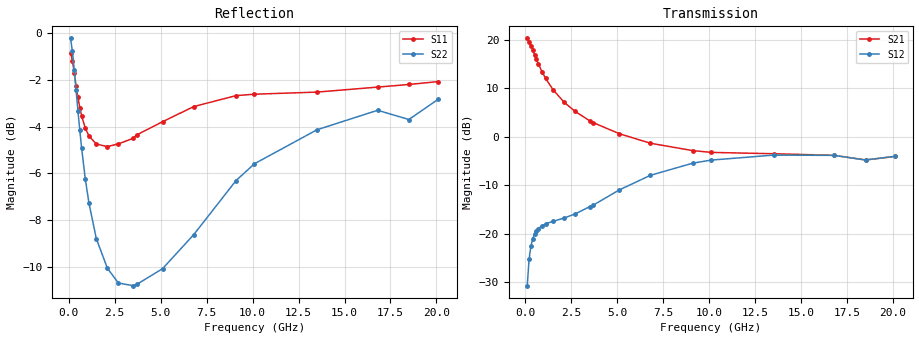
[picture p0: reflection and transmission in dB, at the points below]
!  Infineon Technologies AG
! BFR380L3 , PF131585-7, No.6, Th 09.10.01, soldered on pcb-board, measured with PP GSG850
!  Vce=3.0 V,  Ic=3.0 mA
! Common Emitter S-Parameters:  15. November 2001
#  GHz  S  MA  R  50
! f  S11  S21  S12  S22
! GHz  Mag  Ang  Mag  Ang  Mag  Ang  Mag  Ang
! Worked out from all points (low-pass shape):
!   201 points, 100 MHz to 20.1 GHz, reference 50 ohm
!   highest |S21| = 20.30 dB at 100 MHz (marker M1); lowest = -4.8 dB at 18.5 GHz (marker M2)
!   |S21| within 3 dB of the highest: start of sweep to 459.7 MHz
!   lowest |S11| = -4.9 dB at 2.1 GHz (marker M3), VSWR 3.67, Z = 13.6 - j1.23 ohm
!   |S11| at or under -10 dB: nowhere
!   |S22| runs from -10.8 to -0.2 dB; largest |S21 - S12| = 10
!   S11 on the Smith chart (normalised r, x): 100 MHz: 1.37, -5.05; 400 MHz: 0.35, -1.26; 1.1 GHz: 0.28, -0.36; 3.7 GHz: 0.26, +0.26; 9.1 GHz: 0.33, +1.05; 20.1 GHz: 1.00, +2.55
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0.1  0.9075 -20.9  10.36 165.5  0.02913 76.6  0.9734 -11.8
0.2  0.8728 -40.9  9.564 152.4  0.05449 67.9  0.9131 -22.6
0.3  0.8227 -59.2  8.719 141.0  0.07472 59.2  0.8341 -31.5
0.4  0.7696 -74.3  7.835 131.3  0.08909 52.4  0.7541 -38.6
0.5  0.7287 -87.6  7.012 123.3  0.09963 47.3  0.682 -44.2
0.6  0.6926 -99.1  6.283 116.6  0.1073 43.5  0.6202 -48.5
0.7  0.6647 -109.0  5.676 110.8  0.1131 40.4  0.5681 -51.9
0.9  0.6262 -125.1  4.699 101.5  0.121 36.8  0.4878 -57.2
1.1  0.6026 -138.0  4.002 94.0  0.1267 34.8  0.433 -61.0
1.5  0.5792 -156.9  3.068 82.1  0.1341 34.2  0.3638 -66.8
2.1  0.5718 -176.9  2.278 68.4  0.1453 36.9  0.3147 -75.0
2.7  0.5797 167.9  1.829 57.1  0.1601 41.2  0.2925 -84.5
3.5  0.5954 151.8  1.463 44.3  0.1902 46.1  0.2887 -97.8
3.7  0.6057 148.7  1.397 41.7  0.1978 46.7  0.2906 -102.4
5.1  0.6462 126.8  1.078 24.4  0.2828 47.8  0.3138 -130.1
6.8  0.6962 105.4  0.8579 10.0  0.4007 40.0  0.3711 -165.6
9.1  0.7347 84.1  0.7209 -1.7  0.5344 23.1  0.484 156.0
10.1  0.7398 76.6  0.6906 -5.5  0.575 15.5  0.5256 141.5
13.5  0.7475 58.5  0.6689 -19.1  0.6478 -8.5  0.6211 104.4
16.8  0.7661 47.0  0.6436 -31.0  0.6432 -25.5  0.6836 79.6
18.5  0.776 44.9  0.5768 -38.8  0.5763 -34.2  0.6533 73.3
20.1  0.7872 38.1  0.6274 -42.7  0.6293 -39.4  0.7218 62.0
